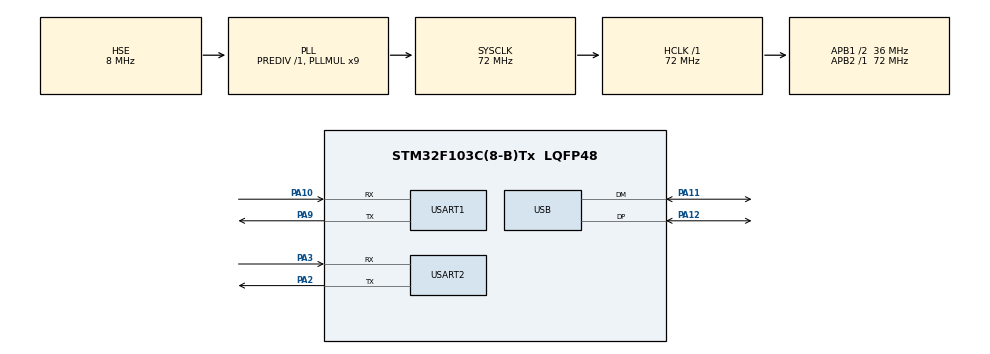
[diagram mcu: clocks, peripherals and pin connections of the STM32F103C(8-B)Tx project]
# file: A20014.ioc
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Dma.Request0=USART1_RX
Dma.Request1=USART1_TX
Dma.Request2=USART2_RX
Dma.Request3=USART2_TX
Dma.USART1_RX.0.Direction=DMA_PERIPH_TO_MEMORY
Dma.USART1_RX.0.Instance=DMA1_Channel5
Dma.USART1_RX.0.MemDataAlignment=DMA_MDATAALIGN_HALFWORD
Dma.USART1_RX.0.MemInc=DMA_MINC_ENABLE
Dma.USART1_RX.0.Mode=DMA_CIRCULAR
Dma.USART1_RX.0.PeriphDataAlignment=DMA_PDATAALIGN_BYTE
Dma.USART1_RX.0.PeriphInc=DMA_PINC_DISABLE
Dma.USART1_RX.0.Priority=DMA_PRIORITY_LOW
Dma.USART1_TX.1.Direction=DMA_MEMORY_TO_PERIPH
Dma.USART1_TX.1.Instance=DMA1_Channel4
Dma.USART1_TX.1.MemDataAlignment=DMA_MDATAALIGN_BYTE
Dma.USART1_TX.1.MemInc=DMA_MINC_ENABLE
Dma.USART1_TX.1.Mode=DMA_NORMAL
Dma.USART1_TX.1.PeriphDataAlignment=DMA_PDATAALIGN_BYTE
Dma.USART1_TX.1.PeriphInc=DMA_PINC_DISABLE
Dma.USART1_TX.1.Priority=DMA_PRIORITY_LOW
Dma.USART2_RX.2.Direction=DMA_PERIPH_TO_MEMORY
Dma.USART2_RX.2.Instance=DMA1_Channel6
Dma.USART2_RX.2.MemDataAlignment=DMA_MDATAALIGN_HALFWORD
Dma.USART2_RX.2.MemInc=DMA_MINC_ENABLE
Dma.USART2_RX.2.Mode=DMA_CIRCULAR
Dma.USART2_RX.2.PeriphDataAlignment=DMA_PDATAALIGN_BYTE
Dma.USART2_RX.2.PeriphInc=DMA_PINC_DISABLE
Dma.USART2_RX.2.Priority=DMA_PRIORITY_LOW
Dma.USART2_TX.3.Direction=DMA_MEMORY_TO_PERIPH
Dma.USART2_TX.3.Instance=DMA1_Channel7
Dma.USART2_TX.3.MemDataAlignment=DMA_MDATAALIGN_BYTE
Dma.USART2_TX.3.MemInc=DMA_MINC_ENABLE
Dma.USART2_TX.3.Mode=DMA_NORMAL
Dma.USART2_TX.3.PeriphDataAlignment=DMA_PDATAALIGN_BYTE
Dma.USART2_TX.3.PeriphInc=DMA_PINC_DISABLE
Dma.USART2_TX.3.Priority=DMA_PRIORITY_LOW
Mcu.Family=STM32F1
Mcu.Name=STM32F103C(8-B)Tx
Mcu.Package=LQFP48
NVIC.DMA1_Channel4_IRQn=true\:0\:0\:false\:false\:true\:false\:true
NVIC.DMA1_Channel5_IRQn=true\:0\:0\:false\:false\:true\:false\:true
NVIC.DMA1_Channel6_IRQn=true\:0\:0\:false\:false\:true\:false\:true
NVIC.DMA1_Channel7_IRQn=true\:0\:0\:false\:false\:true\:false\:true
NVIC.PriorityGroup=NVIC_PRIORITYGROUP_4
NVIC.USART1_IRQn=true\:0\:0\:false\:false\:true\:true\:true
NVIC.USART2_IRQn=true\:0\:0\:false\:false\:true\:true\:true
NVIC.USB_HP_CAN1_TX_IRQn=true\:0\:0\:false\:false\:true\:true\:true
NVIC.USB_LP_CAN1_RX0_IRQn=true\:0\:0\:false\:false\:true\:true\:true
PA10.Mode=Asynchronous
PA10.Signal=USART1_RX
PA11.Mode=Device
PA11.Signal=USB_DM
PA12.Mode=Device
PA12.Signal=USB_DP
PA13.Mode=Serial_Wire
PA13.Signal=SYS_JTMS-SWDIO
PA14.Mode=Serial_Wire
PA14.Signal=SYS_JTCK-SWCLK
PA2.Mode=Asynchronous
PA2.Signal=USART2_TX
PA3.Mode=Asynchronous
PA3.Signal=USART2_RX
PA9.Mode=Asynchronous
PA9.Signal=USART1_TX
PD0-OSC_IN.Mode=HSE-External-Oscillator
PD0-OSC_IN.Signal=RCC_OSC_IN
PD1-OSC_OUT.Mode=HSE-External-Oscillator
PD1-OSC_OUT.Signal=RCC_OSC_OUT
ProjectManager.HeapSize=0x200
ProjectManager.StackSize=0x400
ProjectManager.TargetToolchain=SW4STM32
RCC.AHBFreq_Value=72000000
RCC.APB1CLKDivider=RCC_HCLK_DIV2
RCC.APB1Freq_Value=36000000
RCC.APB1TimFreq_Value=72000000
RCC.APB2Freq_Value=72000000
RCC.APB2TimFreq_Value=72000000
RCC.HCLKFreq_Value=72000000
RCC.PLLMUL=RCC_PLL_MUL9
RCC.PLLSourceVirtual=RCC_PLLSOURCE_HSE
RCC.SYSCLKFreq_VALUE=72000000
RCC.SYSCLKSource=RCC_SYSCLKSOURCE_PLLCLK
RCC.USBFreq_Value=48000000
RCC.USBPrescaler=RCC_USBCLKSOURCE_PLL_DIV1_5
USART1.VirtualMode=VM_ASYNC
USART2.VirtualMode=VM_ASYNC
USB_DEVICE.CLASS_NAME_FS=CDC
USB_DEVICE.VirtualMode=Cdc
USB_DEVICE.VirtualModeFS=Cdc_FS
VP_IWDG_VS_IWDG.Mode=IWDG_Activate
VP_USB_DEVICE_VS_USB_DEVICE_CDC_FS.Mode=CDC_FS
board=custom

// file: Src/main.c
/* USER CODE BEGIN Header */
/**
  ******************************************************************************
  * @file           : main.c
  * @brief          : Main program body
  ******************************************************************************
  * @attention
  *
  * <h2><center>&copy; Copyright (c) 2020 STMicroelectronics.
  * All rights reserved.</center></h2>
  *
  * This software component is licensed by ST under Ultimate Liberty license
  * SLA0044, the "License"; You may not use this file except in compliance with
  * the License. You may obtain a copy of the License at:
  *                             www.st.com/SLA0044
  *
  ******************************************************************************
  */
/* USER CODE END Header */

#include "main.h"
#include "cmsis_os.h"
#include "usb_device.h"

#include "Kernel.h"

IWDG_HandleTypeDef hiwdg;

UART_HandleTypeDef huart1;
UART_HandleTypeDef huart2;
DMA_HandleTypeDef hdma_usart1_rx;
DMA_HandleTypeDef hdma_usart1_tx;
DMA_HandleTypeDef hdma_usart2_rx;
DMA_HandleTypeDef hdma_usart2_tx;

osThreadId tskMainHandle;
osThreadId tskTransmit2UartHandle;

void SystemClock_Config(void);
static void MX_GPIO_Init(void);
static void MX_DMA_Init(void);
static void MX_USART1_UART_Init(void);
static void MX_USART2_UART_Init(void);
static void MX_IWDG_Init(void);
void tskMainStart(void const * argument);
void tskTransmit2UartStart(void const * argument);

int main(void)
{

  /* MCU Configuration--------------------------------------------------------*/

  /* Reset of all peripherals, Initializes the Flash interface and the Systick. */
  HAL_Init();

  /* Configure the system clock */
  SystemClock_Config();

  /* USER CODE BEGIN SysInit */
  __enable_irq();
  /* USER CODE END SysInit */

  /* Initialize all configured peripherals */
  MX_GPIO_Init();
  MX_DMA_Init();
  MX_USART1_UART_Init();
  MX_USART2_UART_Init();
  MX_USB_DEVICE_Init();
  MX_IWDG_Init();
  /* USER CODE BEGIN 2 */

  KernelInit();

  /* USER CODE END 2 */

  /* Create the thread(s) */
  /* definition and creation of tskMain */

  osThreadDef(tskMain, tskMainStart, osPriorityNormal, 0, 128);
  tskMainHandle = osThreadCreate(osThread(tskMain), NULL);

  /* definition and creation of tskTransmit2Uart */
  osThreadDef(tskTransmit2Uart, tskTransmit2UartStart, osPriorityIdle, 0, 128);
  tskTransmit2UartHandle = osThreadCreate(osThread(tskTransmit2Uart), NULL);

  /* Start scheduler */
  osKernelStart();

  /* We should never get here as control is now taken by the scheduler */

  /* init code for USB_DEVICE */
  //MX_USB_DEVICE_Init();

  /* Infinite loop */
  while (1)
  {
  }
}

void SystemClock_Config(void)
{
  RCC_OscInitTypeDef RCC_OscInitStruct = {0};
  RCC_ClkInitTypeDef RCC_ClkInitStruct = {0};
  RCC_PeriphCLKInitTypeDef PeriphClkInit = {0};

  /** Initializes the CPU, AHB and APB busses clocks
  */
  RCC_OscInitStruct.OscillatorType = RCC_OSCILLATORTYPE_LSI|RCC_OSCILLATORTYPE_HSE;
  RCC_OscInitStruct.HSEState = RCC_HSE_ON;
  RCC_OscInitStruct.HSEPredivValue = RCC_HSE_PREDIV_DIV1;
  RCC_OscInitStruct.HSIState = RCC_HSI_ON;
  RCC_OscInitStruct.LSIState = RCC_LSI_ON;
  RCC_OscInitStruct.PLL.PLLState = RCC_PLL_ON;
  RCC_OscInitStruct.PLL.PLLSource = RCC_PLLSOURCE_HSE;
  RCC_OscInitStruct.PLL.PLLMUL = RCC_PLL_MUL9;
  if (HAL_RCC_OscConfig(&RCC_OscInitStruct) != HAL_OK)
  {
    Error_Handler();
  }
  /** Initializes the CPU, AHB and APB busses clocks
  */
  RCC_ClkInitStruct.ClockType = RCC_CLOCKTYPE_HCLK|RCC_CLOCKTYPE_SYSCLK
                              |RCC_CLOCKTYPE_PCLK1|RCC_CLOCKTYPE_PCLK2;
  RCC_ClkInitStruct.SYSCLKSource = RCC_SYSCLKSOURCE_PLLCLK;
  RCC_ClkInitStruct.AHBCLKDivider = RCC_SYSCLK_DIV1;
  RCC_ClkInitStruct.APB1CLKDivider = RCC_HCLK_DIV2;
  RCC_ClkInitStruct.APB2CLKDivider = RCC_HCLK_DIV1;

  if (HAL_RCC_ClockConfig(&RCC_ClkInitStruct, FLASH_LATENCY_2) != HAL_OK)
  {
    Error_Handler();
  }
  PeriphClkInit.PeriphClockSelection = RCC_PERIPHCLK_USB;
  PeriphClkInit.UsbClockSelection = RCC_USBCLKSOURCE_PLL_DIV1_5;
  if (HAL_RCCEx_PeriphCLKConfig(&PeriphClkInit) != HAL_OK)
  {
    Error_Handler();
  }
}

static void MX_IWDG_Init(void)
{

  hiwdg.Instance = IWDG;
  hiwdg.Init.Prescaler = IWDG_PRESCALER_4;
  hiwdg.Init.Reload = 4095;
  if (HAL_IWDG_Init(&hiwdg) != HAL_OK)
  {
    Error_Handler();
  }

}

static void MX_USART1_UART_Init(void)
{

  huart1.Instance = USART1;
  huart1.Init.BaudRate = 9600;
  huart1.Init.WordLength = UART_WORDLENGTH_8B;
  huart1.Init.StopBits = UART_STOPBITS_1;
  huart1.Init.Parity = UART_PARITY_NONE;
  huart1.Init.Mode = UART_MODE_TX_RX;
  huart1.Init.HwFlowCtl = UART_HWCONTROL_NONE;
  huart1.Init.OverSampling = UART_OVERSAMPLING_16;
  if (HAL_UART_Init(&huart1) != HAL_OK)
  {
    Error_Handler();
  }

}

static void MX_USART2_UART_Init(void)
{

  huart2.Instance = USART2;
  huart2.Init.BaudRate = 19200;
  huart2.Init.WordLength = UART_WORDLENGTH_8B;
  huart2.Init.StopBits = UART_STOPBITS_1;
  huart2.Init.Parity = UART_PARITY_NONE;
  huart2.Init.Mode = UART_MODE_TX_RX;
  huart2.Init.HwFlowCtl = UART_HWCONTROL_NONE;
  huart2.Init.OverSampling = UART_OVERSAMPLING_16;
  if (HAL_UART_Init(&huart2) != HAL_OK)
  {
    Error_Handler();
  }

}

static void MX_DMA_Init(void)
{
  /* DMA controller clock enable */
  __HAL_RCC_DMA1_CLK_ENABLE();

  /* DMA interrupt init */
  /* DMA1_Channel4_IRQn interrupt configuration */
  HAL_NVIC_SetPriority(DMA1_Channel4_IRQn, 5, 0);
  HAL_NVIC_EnableIRQ(DMA1_Channel4_IRQn);
  /* DMA1_Channel5_IRQn interrupt configuration */
  HAL_NVIC_SetPriority(DMA1_Channel5_IRQn, 5, 0);
  HAL_NVIC_EnableIRQ(DMA1_Channel5_IRQn);
  /* DMA1_Channel6_IRQn interrupt configuration */
  HAL_NVIC_SetPriority(DMA1_Channel6_IRQn, 5, 0);
  HAL_NVIC_EnableIRQ(DMA1_Channel6_IRQn);
  /* DMA1_Channel7_IRQn interrupt configuration */
  HAL_NVIC_SetPriority(DMA1_Channel7_IRQn, 5, 0);
  HAL_NVIC_EnableIRQ(DMA1_Channel7_IRQn);

}
static void MX_GPIO_Init(void)
{
	  GPIO_InitTypeDef GPIO_InitStruct = {0};

	  /* GPIO Ports Clock Enable */
	  __HAL_RCC_GPIOD_CLK_ENABLE();
	  __HAL_RCC_GPIOA_CLK_ENABLE();
	  __HAL_RCC_GPIOC_CLK_ENABLE();

	  /*Configure GPIO pin Output Level */
	  HAL_GPIO_WritePin(Rs485En_GPIO_Port, Rs485En_Pin, GPIO_PIN_RESET);

	  /*Configure GPIO pin : Rs485En_Pin */
	  GPIO_InitStruct.Pin = Rs485En_Pin;
	  GPIO_InitStruct.Mode = GPIO_MODE_OUTPUT_PP;
	  GPIO_InitStruct.Pull = GPIO_NOPULL;
	  GPIO_InitStruct.Speed = GPIO_SPEED_FREQ_LOW;
	  HAL_GPIO_Init(Rs485En_GPIO_Port, &GPIO_InitStruct);

	  /*Configure GPIO pin Output Level */
	  HAL_GPIO_WritePin(Led_GPIO_Port, Led_Pin, GPIO_PIN_RESET);

	  /*Configure GPIO pin : Led_Pin */
	  GPIO_InitStruct.Pin = Led_Pin;
	  GPIO_InitStruct.Mode = GPIO_MODE_OUTPUT_PP;
	  GPIO_InitStruct.Pull = GPIO_NOPULL;
	  GPIO_InitStruct.Speed = GPIO_SPEED_FREQ_LOW;
	  HAL_GPIO_Init(Led_GPIO_Port, &GPIO_InitStruct);

}

void Error_Handler(void)
{
}

/************************ (C) COPYRIGHT STMicroelectronics *****END OF FILE****/
